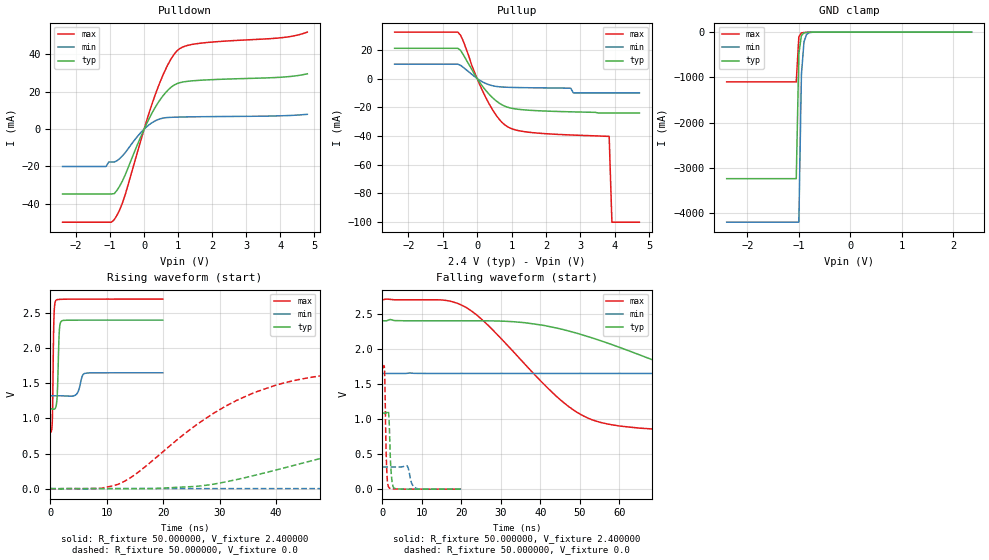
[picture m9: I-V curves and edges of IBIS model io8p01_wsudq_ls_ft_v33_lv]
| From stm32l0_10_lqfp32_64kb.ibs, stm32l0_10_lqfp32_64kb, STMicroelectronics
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|   Model io8p01_wsudq_ls_ft_v33_lv
[Model]  io8p01_wsudq_ls_ft_v33_lv
Model_type I/O
Polarity   Non-Inverting
Enable   Active-Low
Vinl =   0.720000V
Vinh =   1.680000V
Vmeas =  1.200000V
Cref =   50.000000pF
Rref =   100.000000M
Vref =   0.0V
C_comp   2.582000pF   2.574200pF   2.601000pF
[Temperature Range]   25.000000   0.105000k   -40.000000
[Pullup Reference]   2.400000V   1.650000V   2.700000V
[Pulldown Reference]   0.0V   0.0V   0.0V
[POWER Clamp Reference]   2.400000V   1.650000V   2.700000V
[GND Clamp Reference]   0.0V   0.0V   0.0V
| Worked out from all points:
|   slope of the pulldown table from 0 to 0.36 V, typ, clamps not added: 28.5 ohm
|   slope of the pullup table from 0 to 0.36 V, typ, clamps not added: 32.2 ohm
|   GND clamp passes 1 mA (typ) near -0.65 V on its own axis
|   rising waveform, R_fixture 50.000000, V_fixture 2.400000: 20-80 % time 278ps typ, 629ps min, 193ps max; typ from 1.14 V to 2.4 V
|   rising waveform, R_fixture 50.000000, V_fixture 0.0: 20-80 % time 39.7ns typ, 106ns min, 19.4ns max; typ from 0 V to 1.08 V
|   falling waveform, R_fixture 50.000000, V_fixture 2.400000: 20-80 % time 40.7ns typ, 105ns min, 20.1ns max; typ from 2.4 V to 1.14 V
|   falling waveform, R_fixture 50.000000, V_fixture 0.0: 20-80 % time 476ps typ, 851ps min, 375ps max; typ from 1.08 V to 0 V
[Pulldown]
|Voltage   I(typ)   I(min)   I(max)
-2.4V     -34.7mA    -20mA      -49.82mA
-1.12V    -34.7mA    -20mA      -49.82mA
-1.04V    -34.7mA    -17.6mA    -49.82mA
-880mV    -34.55mA   -17.6mA    -48.46mA
-560mV    -24.65mA   -12.68mA   -35.33mA
0V        0A         0A         142fA
400mV     13.84mA    5.066mA    22.03mA
720mV     21.25mA    6.254mA    35.26mA
1.04V     24.82mA    6.464mA    43.03mA
1.6V      26.11mA    6.627mA    45.88mA
4V        27.76mA    7.125mA    48.87mA
4.8V      29.63mA    7.94mA     51.96mA
[Pullup]
|Voltage   I(typ)   I(min)   I(max)
-2.4V     21.07mA    9.995mA    32.35mA
-560mV    21.07mA    9.995mA    32.35mA
-400mV    16.53mA    7.728mA    25.89mA
-80mV     3.011mA    1.496mA    4.671mA
320mV     -10.16mA   -4.078mA   -16.34mA
640mV     -17.08mA   -5.718mA   -28.28mA
960mV     -20.45mA   -6.129mA   -34.49mA
1.76V     -22.39mA   -6.471mA   -37.97mA
2.8V      -23.2mA    -10mA      -39.35mA
3.84V     -24mA      -10mA      -40.2mA
3.92V     -24mA      -10mA      -100mA
4.72V     -24mA      -10mA      -100mA
[GND_clamp]
|Voltage   I(typ)   I(min)   I(max)
-2.4V     -3.237A    -4.198A    -1.1A
-1.05V    -3.237A    -4.198A    -1.1A
-1V       -475.9mA   -4.198A    -104.3mA
-950mV    -76.36mA   -935.5mA   -18.56mA
-900mV    -16.77mA   -213mA     -9.293mA
-850mV    -6.713mA   -51.08mA   -6.724mA
-800mV    -4.108mA   -13.94mA   -4.924mA
-650mV    -1.048mA   -1.2mA     -1.149mA
2.35V     0A         0A         0A
[POWER_clamp]
|Voltage   I(typ)   I(min)   I(max)
-2.4V     0A         0A         0A
0V        0A         0A         0A
[Ramp]
| variable   typ   min   max
dV/dt_r  0.65070/39.66145n   0.18981/0.10645u   1.03800/19.33224n
dV/dt_f  0.75690/40.66003n   0.19476/0.10552u   1.13815/20.04005n
R_load = 50.000000
[Rising Waveform]
R_fixture= 50.000000
V_fixture= 2.400000
V_fixture_min= 1.650000
V_fixture_max= 2.700000
|time   V(typ)   V(min)   V(max)
0s        1.139V     1.322V     800.2mV
360.4ps   1.135V     1.322V     960mV
640.6ps   1.131V     1.322V     2.412V
1.001ns   1.167V     1.322V     2.682V
1.241ns   1.345V     1.322V     2.692V
1.602ns   2.245V     1.323V     2.695V
2.002ns   2.386V     1.322V     2.696V
4.645ns   2.4V       1.345V     2.699V
6.246ns   2.4V       1.643V     2.7V
19.94ns   2.4V       1.65V      2.7V
[Rising Waveform]
R_fixture= 50.000000
V_fixture= 0.0
V_fixture_min= 0.0
V_fixture_max= 0.0
|time   V(typ)   V(min)   V(max)
0s        53.56uV    -246.4nV   268uV
13.01ns   -215.8uV   -46.99uV   98.38mV
27.03ns   41.79mV    -46.26uV   971.6mV
37.04ns   204.9mV    -46.3uV    1.393V
46.05ns   390.8mV    -34.55uV   1.583V
58.06ns   619.8mV    14.84uV    1.682V
82.08ns   909mV      896.4uV    1.723V
120.1ns   1.054V     38.44mV    1.729V
252.3ns   1.085V     266.7mV    1.729V
498.5ns   1.085V     316.6mV    1.729V
[Falling Waveform]
R_fixture= 50.000000
V_fixture= 2.400000
V_fixture_min= 1.650000
V_fixture_max= 2.700000
|time   V(typ)   V(min)   V(max)
0s        2.4V       1.65V      2.7V
15.02ns   2.4V       1.65V      2.698V
21.02ns   2.4V       1.65V      2.597V
48.05ns   2.242V     1.65V      1.144V
55.06ns   2.121V     1.65V      955.1mV
65.07ns   1.917V     1.65V      870.6mV
96.1ns    1.373V     1.65V      813.1mV
139.1ns   1.192V     1.633V     801.7mV
286.3ns   1.14V      1.382V     800.2mV
498.5ns   1.139V     1.322V     800.2mV
[Falling Waveform]
R_fixture= 50.000000
V_fixture= 0.0
V_fixture_min= 0.0
V_fixture_max= 0.0
|time   V(typ)   V(min)   V(max)
0s        1.085V     316.6mV    1.729V
520.5ps   1.085V     316.6mV    1.73V
1.041ns   1.087V     316.6mV    374.1mV
1.281ns   1.106V     316.6mV    115.4mV
1.642ns   1.046V     316.6mV    25.02mV
2.162ns   291.4mV    316.6mV    7.305mV
2.883ns   20.35mV    316.6mV    4.112mV
6.246ns   776uV      332.8mV    432.7uV
9.009ns   176.9uV    4.982mV    249.6uV
19.94ns   53.56uV    -246.4nV   268uV
